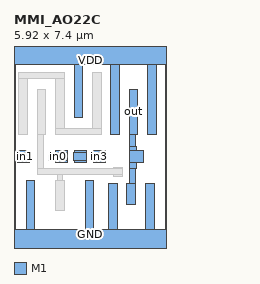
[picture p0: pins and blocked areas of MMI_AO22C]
MACRO MMI_AO22C
	CLASS CORE ;
	FOREIGN MMI_AO22C 0 0 ;
	SIZE 5.92 BY 7.4 ;
	SYMMETRY X Y ;
	SITE CORE1 ;
	PIN out
		DIRECTION output ;
		USE SIGNAL ;
		PORT
			LAYER M1 ;
			RECT 4.48 4.19 4.82 5.95 ;
			LAYER M1 ;
			RECT 4.51 3.735 4.74 4.19 ;
			LAYER M1 ;
			RECT 4.51 3.555 4.755 3.735 ;
			LAYER M1 ;
			RECT 4.51 3.105 5.035 3.555 ;
			LAYER M1 ;
			RECT 4.51 2.85 4.755 3.105 ;
			LAYER M1 ;
			RECT 4.51 2.285 4.74 2.85 ;
			LAYER M1 ;
			RECT 4.4 1.445 4.74 2.285 ;
		END
		AntennaDiffArea 1.4904 ;
	END out
	PIN in1
		DIRECTION input ;
		USE SIGNAL ;
		PORT
			LAYER M1 ;
			RECT 0.145 3.5 0.595 3.555 ;
			LAYER M1 ;
			RECT 0.12 3.16 0.595 3.5 ;
			LAYER M1 ;
			RECT 0.145 3.105 0.595 3.16 ;
		END
		AntennaGateArea 0.6696 ;
	END in1
	PIN GND
		DIRECTION inout ;
		USE GROUND ;
		PORT
			LAYER M1 ;
			RECT 0.47 0.5 0.81 2.4 ;
			LAYER M1 ;
			RECT 2.77 0.5 3.11 2.4 ;
			LAYER M1 ;
			RECT 3.68 0.5 4.02 2.285 ;
			LAYER M1 ;
			RECT 5.12 0.5 5.46 2.285 ;
			LAYER M1 ;
			RECT 0 -0.5 5.92 0.5 ;
		END
	END GND
	PIN in2
		DIRECTION input ;
		USE SIGNAL ;
		PORT
			LAYER M1 ;
			RECT 2.365 3.5 2.815 3.555 ;
			LAYER M1 ;
			RECT 2.305 3.16 2.815 3.5 ;
			LAYER M1 ;
			RECT 2.365 3.105 2.815 3.16 ;
		END
		AntennaGateArea 0.6696 ;
	END in2
	PIN VDD
		DIRECTION inout ;
		USE POWER ;
		PORT
			LAYER M1 ;
			RECT 0 6.9 5.92 7.9 ;
			LAYER M1 ;
			RECT 2.34 4.84 2.68 6.9 ;
			LAYER M1 ;
			RECT 3.76 4.19 4.1 6.9 ;
			LAYER M1 ;
			RECT 5.2 4.19 5.54 6.9 ;
		END
	END VDD
	PIN in3
		DIRECTION input ;
		USE SIGNAL ;
		PORT
			LAYER M1 ;
			RECT 3.105 3.505 3.555 3.555 ;
			LAYER M1 ;
			RECT 3.065 3.165 3.555 3.505 ;
			LAYER M1 ;
			RECT 3.105 3.105 3.555 3.165 ;
		END
		AntennaGateArea 0.6696 ;
	END in3
	PIN in0
		DIRECTION input ;
		USE SIGNAL ;
		PORT
			LAYER M1 ;
			RECT 1.625 3.5 2.075 3.555 ;
			LAYER M1 ;
			RECT 1.36 3.16 2.075 3.5 ;
			LAYER M1 ;
			RECT 1.625 3.105 2.075 3.16 ;
		END
		AntennaGateArea 0.6696 ;
	END in0
	OBS
		LAYER M1 ;
		RECT 0.18 6.36 1.96 6.59 ;
		LAYER M1 ;
		RECT 0.18 4.19 0.52 6.36 ;
		LAYER M1 ;
		RECT 0.9 4.19 1.24 5.94 ;
		LAYER M1 ;
		RECT 1.62 4.42 1.96 6.36 ;
		LAYER M1 ;
		RECT 3.06 4.42 3.4 6.59 ;
		LAYER M1 ;
		RECT 1.62 4.19 3.4 4.42 ;
		LAYER M1 ;
		RECT 0.9 2.86 1.13 4.19 ;
		LAYER M1 ;
		RECT 3.875 2.86 4.215 2.91 ;
		LAYER M1 ;
		RECT 0.9 2.63 4.215 2.86 ;
		LAYER M1 ;
		RECT 1.675 2.4 1.905 2.63 ;
		LAYER M1 ;
		RECT 3.875 2.57 4.215 2.63 ;
		LAYER M1 ;
		RECT 1.62 1.24 1.96 2.4 ;
	END
END MMI_AO22C
